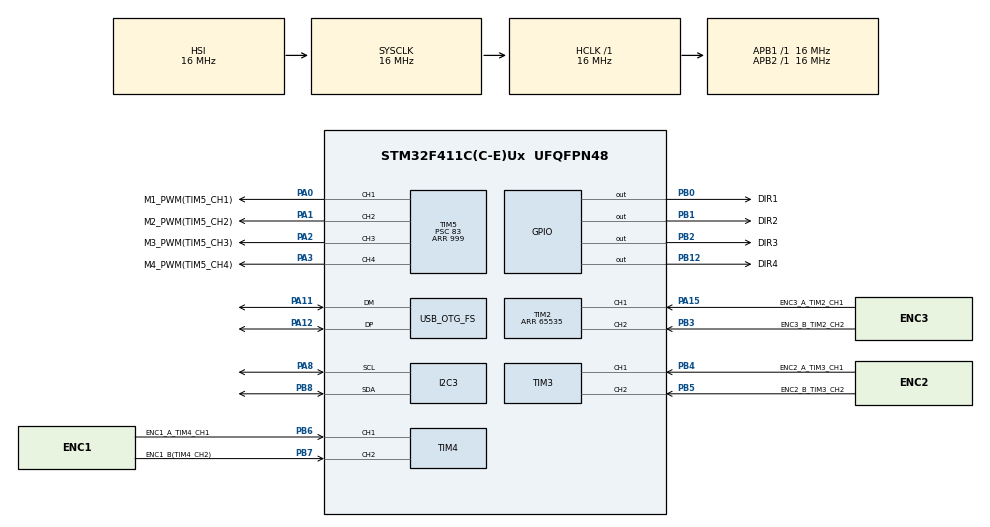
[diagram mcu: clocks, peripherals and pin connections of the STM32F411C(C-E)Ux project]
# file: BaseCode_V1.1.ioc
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Mcu.Family=STM32F4
Mcu.Name=STM32F411C(C-E)Ux
Mcu.Package=UFQFPN48
NVIC.OTG_FS_IRQn=true\:0\:0\:false\:false\:true\:false\:true\:true
NVIC.PriorityGroup=NVIC_PRIORITYGROUP_4
PA0-WKUP.GPIO_Label=M1_PWM(TIM5_CH1)
PA0-WKUP.Signal=S_TIM5_CH1
PA1.GPIO_Label=M2_PWM(TIM5_CH2)
PA1.Signal=S_TIM5_CH2
PA11.Mode=Device_Only
PA11.Signal=USB_OTG_FS_DM
PA12.Mode=Device_Only
PA12.Signal=USB_OTG_FS_DP
PA13.Mode=Serial_Wire
PA13.Signal=SYS_JTMS-SWDIO
PA14.Mode=Serial_Wire
PA14.Signal=SYS_JTCK-SWCLK
PA15.GPIO_Label=ENC3_A_TIM2_CH1
PA15.Signal=S_TIM2_CH1_ETR
PA2.GPIO_Label=M3_PWM(TIM5_CH3)
PA2.Signal=S_TIM5_CH3
PA3.GPIO_Label=M4_PWM(TIM5_CH4)
PA3.Signal=S_TIM5_CH4
PA8.Mode=I2C
PA8.Signal=I2C3_SCL
PB0.GPIO_Label=DIR1
PB0.Signal=GPIO_Output
PB1.GPIO_Label=DIR2
PB1.Signal=GPIO_Output
PB12.GPIO_Label=DIR4
PB12.Signal=GPIO_Output
PB2.GPIO_Label=DIR3
PB2.Signal=GPIO_Output
PB3.GPIO_Label=ENC3_B_TIM2_CH2
PB3.Signal=S_TIM2_CH2
PB4.GPIO_Label=ENC2_A_TIM3_CH1
PB4.Signal=S_TIM3_CH1
PB5.GPIO_Label=ENC2_B_TIM3_CH2
PB5.Signal=S_TIM3_CH2
PB6.GPIO_Label=ENC1_A_TIM4_CH1
PB6.Signal=S_TIM4_CH1
PB7.GPIO_Label=ENC1_B(TIM4_CH2)
PB7.Signal=S_TIM4_CH2
PB8.Mode=I2C
PB8.Signal=I2C3_SDA
PH0\ -\ OSC_IN.Mode=HSE-External-Oscillator
PH0\ -\ OSC_IN.Signal=RCC_OSC_IN
PH1\ -\ OSC_OUT.Mode=HSE-External-Oscillator
PH1\ -\ OSC_OUT.Signal=RCC_OSC_OUT
ProjectManager.HeapSize=0x200
ProjectManager.StackSize=0x400
ProjectManager.TargetToolchain=STM32CubeIDE
RCC.48MHZClocksFreq_Value=48000000
RCC.AHBFreq_Value=16000000
RCC.APB1Freq_Value=16000000
RCC.APB2Freq_Value=16000000
RCC.CortexFreq_Value=16000000
RCC.HSE_VALUE=25000000
RCC.HSI_VALUE=16000000
RCC.LSE_VALUE=32768
RCC.PLLM=15
RCC.PLLN=144
RCC.PLLQ=5
RCC.SYSCLKFreq_VALUE=16000000
RCC.VCOOutputFreq_Value=240000000
SH.S_TIM2_CH1_ETR.0=TIM2_CH1,Encoder_Interface
SH.S_TIM2_CH2.0=TIM2_CH2,Encoder_Interface
SH.S_TIM3_CH1.0=TIM3_CH1,Encoder_Interface
SH.S_TIM3_CH2.0=TIM3_CH2,Encoder_Interface
SH.S_TIM4_CH1.0=TIM4_CH1,Encoder_Interface
SH.S_TIM4_CH2.0=TIM4_CH2,Encoder_Interface
SH.S_TIM5_CH1.0=TIM5_CH1,PWM Generation1 CH1
SH.S_TIM5_CH2.0=TIM5_CH2,PWM Generation2 CH2
SH.S_TIM5_CH3.0=TIM5_CH3,PWM Generation3 CH3
SH.S_TIM5_CH4.0=TIM5_CH4,PWM Generation4 CH4
TIM2.EncoderMode=TIM_ENCODERMODE_TI12
TIM2.IC1Filter=5
TIM2.IC2Filter=5
TIM2.Period=65535
TIM3.EncoderMode=TIM_ENCODERMODE_TI12
TIM3.IC1Filter=5
TIM3.IC2Filter=5
TIM4.EncoderMode=TIM_ENCODERMODE_TI12
TIM4.IC1Filter=5
TIM4.IC2Filter=5
TIM5.Channel-PWM\ Generation1\ CH1=TIM_CHANNEL_1
TIM5.Channel-PWM\ Generation2\ CH2=TIM_CHANNEL_2
TIM5.Channel-PWM\ Generation3\ CH3=TIM_CHANNEL_3
TIM5.Channel-PWM\ Generation4\ CH4=TIM_CHANNEL_4
TIM5.Period=999
TIM5.Prescaler=83
USB_DEVICE.CLASS_NAME_FS=CDC
USB_DEVICE.VirtualMode=Cdc
USB_DEVICE.VirtualModeFS=Cdc_FS
USB_OTG_FS.VirtualMode=Device_Only
VP_TIM5_VS_ClockSourceINT.Mode=Internal
VP_USB_DEVICE_VS_USB_DEVICE_CDC_FS.Mode=CDC_FS
board=custom

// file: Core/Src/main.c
/* USER CODE BEGIN Header */
/**
  ******************************************************************************
  * @file           : main.c
  * @brief          : Main program body (Ultra-Clean Version)
  ******************************************************************************
  */
/* USER CODE END Header */
#include "main.h"
#include "usb_device.h"

/* USER CODE BEGIN Includes */
#include "robot.h"
#include "usbd_cdc_if.h"
#include <stdio.h>
#include <string.h>
/* USER CODE END Includes */

I2C_HandleTypeDef hi2c3;

TIM_HandleTypeDef htim2;
TIM_HandleTypeDef htim3;
TIM_HandleTypeDef htim4;
TIM_HandleTypeDef htim5;

void SystemClock_Config(void);
static void MX_GPIO_Init(void);
static void MX_TIM2_Init(void);
static void MX_TIM3_Init(void);
static void MX_TIM4_Init(void);
static void MX_TIM5_Init(void);
static void MX_I2C3_Init(void);

int main(void)
{

  /* MCU Configuration--------------------------------------------------------*/

  /* Reset of all peripherals, Initializes the Flash interface and the Systick. */
  HAL_Init();

  /* Configure the system clock */
  SystemClock_Config();

  /* Initialize all configured peripherals */
  MX_GPIO_Init();
  MX_TIM2_Init();
  MX_TIM3_Init();
  MX_TIM4_Init();
  MX_TIM5_Init();
  MX_USB_DEVICE_Init();
  MX_I2C3_Init();
  /* USER CODE BEGIN 2 */
  HAL_Delay(1000); /* Allow USB CDC and peripherals to initialize */

  /* Initialize autonomous robot subsystems (Encoders, MD30C Motors, BNO085) */
  robot_init();
  /* USER CODE END 2 */

  /* Infinite loop */
  /* USER CODE BEGIN WHILE */
  while (1)
  {
    /* Service odometry, IMU, motor safety, and USB CDC JSON telemetry */
    robot_loop();
    /* USER CODE END WHILE */

  }
}

void SystemClock_Config(void)
{
  RCC_OscInitTypeDef RCC_OscInitStruct = {0};
  RCC_ClkInitTypeDef RCC_ClkInitStruct = {0};

  /** Configure the main internal regulator output voltage
  */
  __HAL_RCC_PWR_CLK_ENABLE();
  __HAL_PWR_VOLTAGESCALING_CONFIG(PWR_REGULATOR_VOLTAGE_SCALE1);

  /** Initializes the RCC Oscillators according to the specified parameters
  * in the RCC_OscInitTypeDef structure.
  */
  RCC_OscInitStruct.OscillatorType = RCC_OSCILLATORTYPE_HSI|RCC_OSCILLATORTYPE_HSE;
  RCC_OscInitStruct.HSEState = RCC_HSE_ON;
  RCC_OscInitStruct.HSIState = RCC_HSI_ON;
  RCC_OscInitStruct.HSICalibrationValue = RCC_HSICALIBRATION_DEFAULT;
  RCC_OscInitStruct.PLL.PLLState = RCC_PLL_ON;
  RCC_OscInitStruct.PLL.PLLSource = RCC_PLLSOURCE_HSE;
  RCC_OscInitStruct.PLL.PLLM = 15;
  RCC_OscInitStruct.PLL.PLLN = 144;
  RCC_OscInitStruct.PLL.PLLP = RCC_PLLP_DIV2;
  RCC_OscInitStruct.PLL.PLLQ = 5;
  if (HAL_RCC_OscConfig(&RCC_OscInitStruct) != HAL_OK)
  {
    Error_Handler();
  }

  /** Initializes the CPU, AHB and APB buses clocks
  */
  RCC_ClkInitStruct.ClockType = RCC_CLOCKTYPE_HCLK|RCC_CLOCKTYPE_SYSCLK
                              |RCC_CLOCKTYPE_PCLK1|RCC_CLOCKTYPE_PCLK2;
  RCC_ClkInitStruct.SYSCLKSource = RCC_SYSCLKSOURCE_HSI;
  RCC_ClkInitStruct.AHBCLKDivider = RCC_SYSCLK_DIV1;
  RCC_ClkInitStruct.APB1CLKDivider = RCC_HCLK_DIV1;
  RCC_ClkInitStruct.APB2CLKDivider = RCC_HCLK_DIV1;

  if (HAL_RCC_ClockConfig(&RCC_ClkInitStruct, FLASH_LATENCY_0) != HAL_OK)
  {
    Error_Handler();
  }
}

static void MX_I2C3_Init(void)
{

  hi2c3.Instance = I2C3;
  hi2c3.Init.ClockSpeed = 100000;
  hi2c3.Init.DutyCycle = I2C_DUTYCYCLE_2;
  hi2c3.Init.OwnAddress1 = 0;
  hi2c3.Init.AddressingMode = I2C_ADDRESSINGMODE_7BIT;
  hi2c3.Init.DualAddressMode = I2C_DUALADDRESS_DISABLE;
  hi2c3.Init.OwnAddress2 = 0;
  hi2c3.Init.GeneralCallMode = I2C_GENERALCALL_DISABLE;
  hi2c3.Init.NoStretchMode = I2C_NOSTRETCH_DISABLE;
  if (HAL_I2C_Init(&hi2c3) != HAL_OK)
  {
    Error_Handler();
  }

}

static void MX_TIM2_Init(void)
{

  TIM_Encoder_InitTypeDef sConfig = {0};
  TIM_MasterConfigTypeDef sMasterConfig = {0};

  htim2.Instance = TIM2;
  htim2.Init.Prescaler = 0;
  htim2.Init.CounterMode = TIM_COUNTERMODE_UP;
  htim2.Init.Period = 65535;
  htim2.Init.ClockDivision = TIM_CLOCKDIVISION_DIV1;
  htim2.Init.AutoReloadPreload = TIM_AUTORELOAD_PRELOAD_DISABLE;
  sConfig.EncoderMode = TIM_ENCODERMODE_TI12;
  sConfig.IC1Polarity = TIM_ICPOLARITY_RISING;
  sConfig.IC1Selection = TIM_ICSELECTION_DIRECTTI;
  sConfig.IC1Prescaler = TIM_ICPSC_DIV1;
  sConfig.IC1Filter = 5;
  sConfig.IC2Polarity = TIM_ICPOLARITY_RISING;
  sConfig.IC2Selection = TIM_ICSELECTION_DIRECTTI;
  sConfig.IC2Prescaler = TIM_ICPSC_DIV1;
  sConfig.IC2Filter = 5;
  if (HAL_TIM_Encoder_Init(&htim2, &sConfig) != HAL_OK)
  {
    Error_Handler();
  }
  sMasterConfig.MasterOutputTrigger = TIM_TRGO_RESET;
  sMasterConfig.MasterSlaveMode = TIM_MASTERSLAVEMODE_DISABLE;
  if (HAL_TIMEx_MasterConfigSynchronization(&htim2, &sMasterConfig) != HAL_OK)
  {
    Error_Handler();
  }

}

static void MX_TIM3_Init(void)
{

  TIM_Encoder_InitTypeDef sConfig = {0};
  TIM_MasterConfigTypeDef sMasterConfig = {0};

  htim3.Instance = TIM3;
  htim3.Init.Prescaler = 0;
  htim3.Init.CounterMode = TIM_COUNTERMODE_UP;
  htim3.Init.Period = 65535;
  htim3.Init.ClockDivision = TIM_CLOCKDIVISION_DIV1;
  htim3.Init.AutoReloadPreload = TIM_AUTORELOAD_PRELOAD_DISABLE;
  sConfig.EncoderMode = TIM_ENCODERMODE_TI12;
  sConfig.IC1Polarity = TIM_ICPOLARITY_RISING;
  sConfig.IC1Selection = TIM_ICSELECTION_DIRECTTI;
  sConfig.IC1Prescaler = TIM_ICPSC_DIV1;
  sConfig.IC1Filter = 5;
  sConfig.IC2Polarity = TIM_ICPOLARITY_RISING;
  sConfig.IC2Selection = TIM_ICSELECTION_DIRECTTI;
  sConfig.IC2Prescaler = TIM_ICPSC_DIV1;
  sConfig.IC2Filter = 5;
  if (HAL_TIM_Encoder_Init(&htim3, &sConfig) != HAL_OK)
  {
    Error_Handler();
  }
  sMasterConfig.MasterOutputTrigger = TIM_TRGO_RESET;
  sMasterConfig.MasterSlaveMode = TIM_MASTERSLAVEMODE_DISABLE;
  if (HAL_TIMEx_MasterConfigSynchronization(&htim3, &sMasterConfig) != HAL_OK)
  {
    Error_Handler();
  }

}

static void MX_TIM4_Init(void)
{

  TIM_Encoder_InitTypeDef sConfig = {0};
  TIM_MasterConfigTypeDef sMasterConfig = {0};

  htim4.Instance = TIM4;
  htim4.Init.Prescaler = 0;
  htim4.Init.CounterMode = TIM_COUNTERMODE_UP;
  htim4.Init.Period = 65535;
  htim4.Init.ClockDivision = TIM_CLOCKDIVISION_DIV1;
  htim4.Init.AutoReloadPreload = TIM_AUTORELOAD_PRELOAD_DISABLE;
  sConfig.EncoderMode = TIM_ENCODERMODE_TI12;
  sConfig.IC1Polarity = TIM_ICPOLARITY_RISING;
  sConfig.IC1Selection = TIM_ICSELECTION_DIRECTTI;
  sConfig.IC1Prescaler = TIM_ICPSC_DIV1;
  sConfig.IC1Filter = 5;
  sConfig.IC2Polarity = TIM_ICPOLARITY_RISING;
  sConfig.IC2Selection = TIM_ICSELECTION_DIRECTTI;
  sConfig.IC2Prescaler = TIM_ICPSC_DIV1;
  sConfig.IC2Filter = 5;
  if (HAL_TIM_Encoder_Init(&htim4, &sConfig) != HAL_OK)
  {
    Error_Handler();
  }
  sMasterConfig.MasterOutputTrigger = TIM_TRGO_RESET;
  sMasterConfig.MasterSlaveMode = TIM_MASTERSLAVEMODE_DISABLE;
  if (HAL_TIMEx_MasterConfigSynchronization(&htim4, &sMasterConfig) != HAL_OK)
  {
    Error_Handler();
  }

}

static void MX_TIM5_Init(void)
{

  TIM_ClockConfigTypeDef sClockSourceConfig = {0};
  TIM_MasterConfigTypeDef sMasterConfig = {0};
  TIM_OC_InitTypeDef sConfigOC = {0};

  htim5.Instance = TIM5;
  htim5.Init.Prescaler = 83;
  htim5.Init.CounterMode = TIM_COUNTERMODE_UP;
  htim5.Init.Period = 999;
  htim5.Init.ClockDivision = TIM_CLOCKDIVISION_DIV1;
  htim5.Init.AutoReloadPreload = TIM_AUTORELOAD_PRELOAD_DISABLE;
  if (HAL_TIM_Base_Init(&htim5) != HAL_OK)
  {
    Error_Handler();
  }
  sClockSourceConfig.ClockSource = TIM_CLOCKSOURCE_INTERNAL;
  if (HAL_TIM_ConfigClockSource(&htim5, &sClockSourceConfig) != HAL_OK)
  {
    Error_Handler();
  }
  if (HAL_TIM_PWM_Init(&htim5) != HAL_OK)
  {
    Error_Handler();
  }
  sMasterConfig.MasterOutputTrigger = TIM_TRGO_RESET;
  sMasterConfig.MasterSlaveMode = TIM_MASTERSLAVEMODE_DISABLE;
  if (HAL_TIMEx_MasterConfigSynchronization(&htim5, &sMasterConfig) != HAL_OK)
  {
    Error_Handler();
  }
  sConfigOC.OCMode = TIM_OCMODE_PWM1;
  sConfigOC.Pulse = 0;
  sConfigOC.OCPolarity = TIM_OCPOLARITY_HIGH;
  sConfigOC.OCFastMode = TIM_OCFAST_DISABLE;
  if (HAL_TIM_PWM_ConfigChannel(&htim5, &sConfigOC, TIM_CHANNEL_1) != HAL_OK)
  {
    Error_Handler();
  }
  if (HAL_TIM_PWM_ConfigChannel(&htim5, &sConfigOC, TIM_CHANNEL_2) != HAL_OK)
  {
    Error_Handler();
  }
  if (HAL_TIM_PWM_ConfigChannel(&htim5, &sConfigOC, TIM_CHANNEL_3) != HAL_OK)
  {
    Error_Handler();
  }
  if (HAL_TIM_PWM_ConfigChannel(&htim5, &sConfigOC, TIM_CHANNEL_4) != HAL_OK)
  {
    Error_Handler();
  }
  HAL_TIM_MspPostInit(&htim5);

}

static void MX_GPIO_Init(void)
{
  GPIO_InitTypeDef GPIO_InitStruct = {0};

  /* GPIO Ports Clock Enable */
  __HAL_RCC_GPIOH_CLK_ENABLE();
  __HAL_RCC_GPIOA_CLK_ENABLE();
  __HAL_RCC_GPIOB_CLK_ENABLE();

  /*Configure GPIO pin Output Level */
  HAL_GPIO_WritePin(GPIOB, DIR1_Pin|DIR2_Pin|DIR3_Pin|DIR4_Pin|GPIO_PIN_10|GPIO_PIN_15, GPIO_PIN_RESET);

  /*Configure GPIO pins : DIR1_Pin DIR2_Pin DIR3_Pin DIR4_Pin, plus PB10 & PB15 for M3 DIR fallback */
  GPIO_InitStruct.Pin = DIR1_Pin|DIR2_Pin|DIR3_Pin|DIR4_Pin|GPIO_PIN_10|GPIO_PIN_15;
  GPIO_InitStruct.Mode = GPIO_MODE_OUTPUT_PP;
  GPIO_InitStruct.Pull = GPIO_NOPULL;
  GPIO_InitStruct.Speed = GPIO_SPEED_FREQ_LOW;
  HAL_GPIO_Init(GPIOB, &GPIO_InitStruct);

}

void Error_Handler(void)
{
  __disable_irq();
  while (1)
  {
  }
}
